VERSION 5.4 ;
NAMESCASESENSITIVE ON ;
BUSBITCHARS "[]" ;
DIVIDERCHAR "/" ;
UNITS
  DATABASE MICRONS 2000 ;
END UNITS
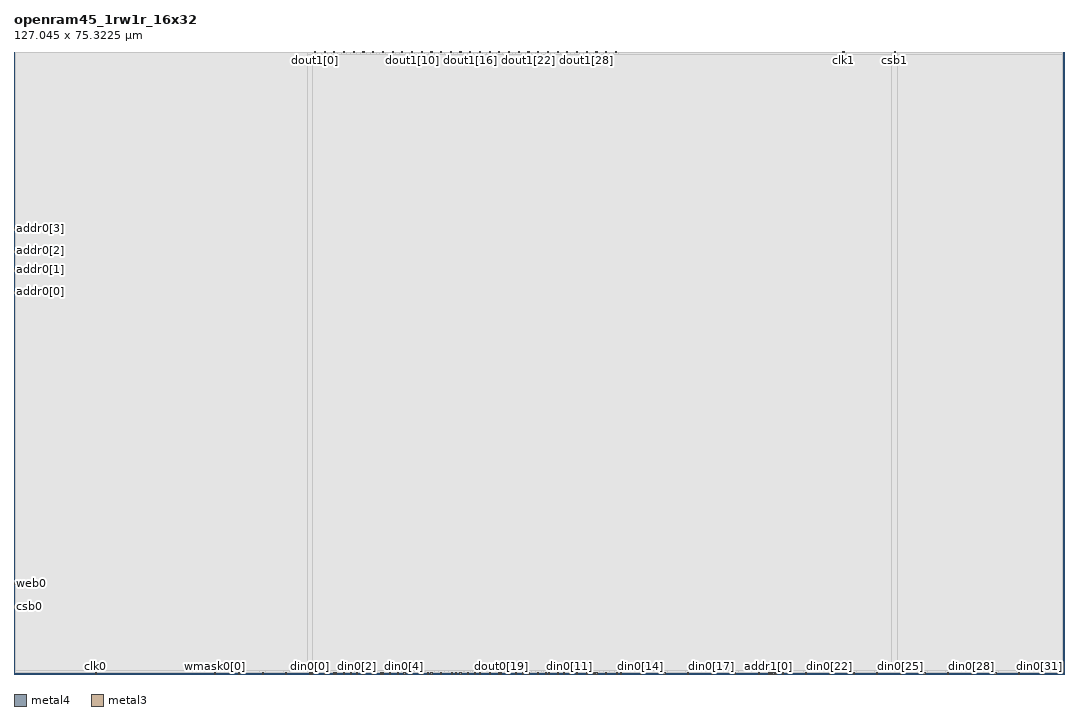
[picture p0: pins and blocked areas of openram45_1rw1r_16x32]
MACRO openram45_1rw1r_16x32
   CLASS BLOCK ;
   SIZE 127.045 BY 75.3225 ;
   SYMMETRY X Y R90 ;
   PIN din0[0]
      DIRECTION INPUT ;
      PORT
         LAYER metal4 ;
         RECT  35.7375 0.0 35.8775 0.14 ;
      END
   END din0[0]
   PIN din0[1]
      DIRECTION INPUT ;
      PORT
         LAYER metal4 ;
         RECT  38.5975 0.0 38.7375 0.14 ;
      END
   END din0[1]
   PIN din0[2]
      DIRECTION INPUT ;
      PORT
         LAYER metal4 ;
         RECT  41.4575 0.0 41.5975 0.14 ;
      END
   END din0[2]
   PIN din0[3]
      DIRECTION INPUT ;
      PORT
         LAYER metal4 ;
         RECT  44.3175 0.0 44.4575 0.14 ;
      END
   END din0[3]
   PIN din0[4]
      DIRECTION INPUT ;
      PORT
         LAYER metal4 ;
         RECT  47.1775 0.0 47.3175 0.14 ;
      END
   END din0[4]
   PIN din0[5]
      DIRECTION INPUT ;
      PORT
         LAYER metal4 ;
         RECT  50.0375 0.0 50.1775 0.14 ;
      END
   END din0[5]
   PIN din0[6]
      DIRECTION INPUT ;
      PORT
         LAYER metal4 ;
         RECT  52.8975 0.0 53.0375 0.14 ;
      END
   END din0[6]
   PIN din0[7]
      DIRECTION INPUT ;
      PORT
         LAYER metal4 ;
         RECT  55.7575 0.0 55.8975 0.14 ;
      END
   END din0[7]
   PIN din0[8]
      DIRECTION INPUT ;
      PORT
         LAYER metal4 ;
         RECT  58.6175 0.0 58.7575 0.14 ;
      END
   END din0[8]
   PIN din0[9]
      DIRECTION INPUT ;
      PORT
         LAYER metal4 ;
         RECT  61.4775 0.0 61.6175 0.14 ;
      END
   END din0[9]
   PIN din0[10]
      DIRECTION INPUT ;
      PORT
         LAYER metal4 ;
         RECT  64.3375 0.0 64.4775 0.14 ;
      END
   END din0[10]
   PIN din0[11]
      DIRECTION INPUT ;
      PORT
         LAYER metal4 ;
         RECT  67.1975 0.0 67.3375 0.14 ;
      END
   END din0[11]
   PIN din0[12]
      DIRECTION INPUT ;
      PORT
         LAYER metal4 ;
         RECT  70.0575 0.0 70.1975 0.14 ;
      END
   END din0[12]
   PIN din0[13]
      DIRECTION INPUT ;
      PORT
         LAYER metal4 ;
         RECT  72.9175 0.0 73.0575 0.14 ;
      END
   END din0[13]
   PIN din0[14]
      DIRECTION INPUT ;
      PORT
         LAYER metal4 ;
         RECT  75.7775 0.0 75.9175 0.14 ;
      END
   END din0[14]
   PIN din0[15]
      DIRECTION INPUT ;
      PORT
         LAYER metal4 ;
         RECT  78.6375 0.0 78.7775 0.14 ;
      END
   END din0[15]
   PIN din0[16]
      DIRECTION INPUT ;
      PORT
         LAYER metal4 ;
         RECT  81.4975 0.0 81.6375 0.14 ;
      END
   END din0[16]
   PIN din0[17]
      DIRECTION INPUT ;
      PORT
         LAYER metal4 ;
         RECT  84.3575 0.0 84.4975 0.14 ;
      END
   END din0[17]
   PIN din0[18]
      DIRECTION INPUT ;
      PORT
         LAYER metal4 ;
         RECT  87.2175 0.0 87.3575 0.14 ;
      END
   END din0[18]
   PIN din0[19]
      DIRECTION INPUT ;
      PORT
         LAYER metal4 ;
         RECT  90.0775 0.0 90.2175 0.14 ;
      END
   END din0[19]
   PIN din0[20]
      DIRECTION INPUT ;
      PORT
         LAYER metal4 ;
         RECT  92.9375 0.0 93.0775 0.14 ;
      END
   END din0[20]
   PIN din0[21]
      DIRECTION INPUT ;
      PORT
         LAYER metal4 ;
         RECT  95.7975 0.0 95.9375 0.14 ;
      END
   END din0[21]
   PIN din0[22]
      DIRECTION INPUT ;
      PORT
         LAYER metal4 ;
         RECT  98.6575 0.0 98.7975 0.14 ;
      END
   END din0[22]
   PIN din0[23]
      DIRECTION INPUT ;
      PORT
         LAYER metal4 ;
         RECT  101.5175 0.0 101.6575 0.14 ;
      END
   END din0[23]
   PIN din0[24]
      DIRECTION INPUT ;
      PORT
         LAYER metal4 ;
         RECT  104.3775 0.0 104.5175 0.14 ;
      END
   END din0[24]
   PIN din0[25]
      DIRECTION INPUT ;
      PORT
         LAYER metal4 ;
         RECT  107.2375 0.0 107.3775 0.14 ;
      END
   END din0[25]
   PIN din0[26]
      DIRECTION INPUT ;
      PORT
         LAYER metal4 ;
         RECT  110.0975 0.0 110.2375 0.14 ;
      END
   END din0[26]
   PIN din0[27]
      DIRECTION INPUT ;
      PORT
         LAYER metal4 ;
         RECT  112.9575 0.0 113.0975 0.14 ;
      END
   END din0[27]
   PIN din0[28]
      DIRECTION INPUT ;
      PORT
         LAYER metal4 ;
         RECT  115.8175 0.0 115.9575 0.14 ;
      END
   END din0[28]
   PIN din0[29]
      DIRECTION INPUT ;
      PORT
         LAYER metal4 ;
         RECT  118.6775 0.0 118.8175 0.14 ;
      END
   END din0[29]
   PIN din0[30]
      DIRECTION INPUT ;
      PORT
         LAYER metal4 ;
         RECT  121.5375 0.0 121.6775 0.14 ;
      END
   END din0[30]
   PIN din0[31]
      DIRECTION INPUT ;
      PORT
         LAYER metal4 ;
         RECT  124.3975 0.0 124.5375 0.14 ;
      END
   END din0[31]
   PIN addr0[0]
      DIRECTION INPUT ;
      PORT
         LAYER metal3 ;
         RECT  0.0 46.1875 0.14 46.3275 ;
      END
   END addr0[0]
   PIN addr0[1]
      DIRECTION INPUT ;
      PORT
         LAYER metal3 ;
         RECT  0.0 48.9175 0.14 49.0575 ;
      END
   END addr0[1]
   PIN addr0[2]
      DIRECTION INPUT ;
      PORT
         LAYER metal3 ;
         RECT  0.0 51.1275 0.14 51.2675 ;
      END
   END addr0[2]
   PIN addr0[3]
      DIRECTION INPUT ;
      PORT
         LAYER metal3 ;
         RECT  0.0 53.8575 0.14 53.9975 ;
      END
   END addr0[3]
   PIN addr1[0]
      DIRECTION INPUT ;
      PORT
         LAYER metal4 ;
         RECT  91.265 0.0 91.405 0.14 ;
      END
   END addr1[0]
   PIN addr1[1]
      DIRECTION INPUT ;
      PORT
         LAYER metal4 ;
         RECT  92.12 0.0 92.26 0.14 ;
      END
   END addr1[1]
   PIN addr1[2]
      DIRECTION INPUT ;
      PORT
         LAYER metal4 ;
         RECT  91.55 0.0 91.69 0.14 ;
      END
   END addr1[2]
   PIN addr1[3]
      DIRECTION INPUT ;
      PORT
         LAYER metal4 ;
         RECT  91.835 0.0 91.975 0.14 ;
      END
   END addr1[3]
   PIN csb0
      DIRECTION INPUT ;
      PORT
         LAYER metal3 ;
         RECT  0.0 8.0975 0.14 8.2375 ;
      END
   END csb0
   PIN csb1
      DIRECTION INPUT ;
      PORT
         LAYER metal4 ;
         RECT  106.4975 75.1825 106.6375 75.3225 ;
      END
   END csb1
   PIN web0
      DIRECTION INPUT ;
      PORT
         LAYER metal3 ;
         RECT  0.0 10.8275 0.14 10.9675 ;
      END
   END web0
   PIN clk0
      DIRECTION INPUT ;
      PORT
         LAYER metal4 ;
         RECT  9.84 0.0 9.98 0.14 ;
      END
   END clk0
   PIN clk1
      DIRECTION INPUT ;
      PORT
         LAYER metal4 ;
         RECT  100.3 75.1825 100.44 75.3225 ;
      END
   END clk1
   PIN wmask0[0]
      DIRECTION INPUT ;
      PORT
         LAYER metal4 ;
         RECT  24.2975 0.0 24.4375 0.14 ;
      END
   END wmask0[0]
   PIN wmask0[1]
      DIRECTION INPUT ;
      PORT
         LAYER metal4 ;
         RECT  27.1575 0.0 27.2975 0.14 ;
      END
   END wmask0[1]
   PIN wmask0[2]
      DIRECTION INPUT ;
      PORT
         LAYER metal4 ;
         RECT  30.0175 0.0 30.1575 0.14 ;
      END
   END wmask0[2]
   PIN wmask0[3]
      DIRECTION INPUT ;
      PORT
         LAYER metal4 ;
         RECT  32.8775 0.0 33.0175 0.14 ;
      END
   END wmask0[3]
   PIN dout0[0]
      DIRECTION OUTPUT ;
      PORT
         LAYER metal4 ;
         RECT  36.025 0.0 36.165 0.14 ;
      END
   END dout0[0]
   PIN dout0[1]
      DIRECTION OUTPUT ;
      PORT
         LAYER metal4 ;
         RECT  37.5125 0.0 37.6525 0.14 ;
      END
   END dout0[1]
   PIN dout0[2]
      DIRECTION OUTPUT ;
      PORT
         LAYER metal4 ;
         RECT  38.8825 0.0 39.0225 0.14 ;
      END
   END dout0[2]
   PIN dout0[3]
      DIRECTION OUTPUT ;
      PORT
         LAYER metal4 ;
         RECT  39.8625 0.0 40.0025 0.14 ;
      END
   END dout0[3]
   PIN dout0[4]
      DIRECTION OUTPUT ;
      PORT
         LAYER metal4 ;
         RECT  40.7 0.0 40.84 0.14 ;
      END
   END dout0[4]
   PIN dout0[5]
      DIRECTION OUTPUT ;
      PORT
         LAYER metal4 ;
         RECT  42.2125 0.0 42.3525 0.14 ;
      END
   END dout0[5]
   PIN dout0[6]
      DIRECTION OUTPUT ;
      PORT
         LAYER metal4 ;
         RECT  43.3875 0.0 43.5275 0.14 ;
      END
   END dout0[6]
   PIN dout0[7]
      DIRECTION OUTPUT ;
      PORT
         LAYER metal4 ;
         RECT  44.6025 0.0 44.7425 0.14 ;
      END
   END dout0[7]
   PIN dout0[8]
      DIRECTION OUTPUT ;
      PORT
         LAYER metal4 ;
         RECT  45.425 0.0 45.565 0.14 ;
      END
   END dout0[8]
   PIN dout0[9]
      DIRECTION OUTPUT ;
      PORT
         LAYER metal4 ;
         RECT  46.42 0.0 46.56 0.14 ;
      END
   END dout0[9]
   PIN dout0[10]
      DIRECTION OUTPUT ;
      PORT
         LAYER metal4 ;
         RECT  48.0875 0.0 48.2275 0.14 ;
      END
   END dout0[10]
   PIN dout0[11]
      DIRECTION OUTPUT ;
      PORT
         LAYER metal4 ;
         RECT  49.2625 0.0 49.4025 0.14 ;
      END
   END dout0[11]
   PIN dout0[12]
      DIRECTION OUTPUT ;
      PORT
         LAYER metal4 ;
         RECT  50.4375 0.0 50.5775 0.14 ;
      END
   END dout0[12]
   PIN dout0[13]
      DIRECTION OUTPUT ;
      PORT
         LAYER metal4 ;
         RECT  51.6125 0.0 51.7525 0.14 ;
      END
   END dout0[13]
   PIN dout0[14]
      DIRECTION OUTPUT ;
      PORT
         LAYER metal4 ;
         RECT  53.36 0.0 53.5 0.14 ;
      END
   END dout0[14]
   PIN dout0[15]
      DIRECTION OUTPUT ;
      PORT
         LAYER metal4 ;
         RECT  53.9625 0.0 54.1025 0.14 ;
      END
   END dout0[15]
   PIN dout0[16]
      DIRECTION OUTPUT ;
      PORT
         LAYER metal4 ;
         RECT  54.825 0.0 54.965 0.14 ;
      END
   END dout0[16]
   PIN dout0[17]
      DIRECTION OUTPUT ;
      PORT
         LAYER metal4 ;
         RECT  56.3125 0.0 56.4525 0.14 ;
      END
   END dout0[17]
   PIN dout0[18]
      DIRECTION OUTPUT ;
      PORT
         LAYER metal4 ;
         RECT  57.4875 0.0 57.6275 0.14 ;
      END
   END dout0[18]
   PIN dout0[19]
      DIRECTION OUTPUT ;
      PORT
         LAYER metal4 ;
         RECT  58.9025 0.0 59.0425 0.14 ;
      END
   END dout0[19]
   PIN dout0[20]
      DIRECTION OUTPUT ;
      PORT
         LAYER metal4 ;
         RECT  59.8375 0.0 59.9775 0.14 ;
      END
   END dout0[20]
   PIN dout0[21]
      DIRECTION OUTPUT ;
      PORT
         LAYER metal4 ;
         RECT  60.72 0.0 60.86 0.14 ;
      END
   END dout0[21]
   PIN dout0[22]
      DIRECTION OUTPUT ;
      PORT
         LAYER metal4 ;
         RECT  62.1875 0.0 62.3275 0.14 ;
      END
   END dout0[22]
   PIN dout0[23]
      DIRECTION OUTPUT ;
      PORT
         LAYER metal4 ;
         RECT  63.3625 0.0 63.5025 0.14 ;
      END
   END dout0[23]
   PIN dout0[24]
      DIRECTION OUTPUT ;
      PORT
         LAYER metal4 ;
         RECT  64.6225 0.0 64.7625 0.14 ;
      END
   END dout0[24]
   PIN dout0[25]
      DIRECTION OUTPUT ;
      PORT
         LAYER metal4 ;
         RECT  65.7125 0.0 65.8525 0.14 ;
      END
   END dout0[25]
   PIN dout0[26]
      DIRECTION OUTPUT ;
      PORT
         LAYER metal4 ;
         RECT  66.44 0.0 66.58 0.14 ;
      END
   END dout0[26]
   PIN dout0[27]
      DIRECTION OUTPUT ;
      PORT
         LAYER metal4 ;
         RECT  68.0625 0.0 68.2025 0.14 ;
      END
   END dout0[27]
   PIN dout0[28]
      DIRECTION OUTPUT ;
      PORT
         LAYER metal4 ;
         RECT  69.2375 0.0 69.3775 0.14 ;
      END
   END dout0[28]
   PIN dout0[29]
      DIRECTION OUTPUT ;
      PORT
         LAYER metal4 ;
         RECT  70.4125 0.0 70.5525 0.14 ;
      END
   END dout0[29]
   PIN dout0[30]
      DIRECTION OUTPUT ;
      PORT
         LAYER metal4 ;
         RECT  71.5875 0.0 71.7275 0.14 ;
      END
   END dout0[30]
   PIN dout0[31]
      DIRECTION OUTPUT ;
      PORT
         LAYER metal4 ;
         RECT  73.335 0.0 73.475 0.14 ;
      END
   END dout0[31]
   PIN dout1[0]
      DIRECTION OUTPUT ;
      PORT
         LAYER metal4 ;
         RECT  36.3375 75.1825 36.4775 75.3225 ;
      END
   END dout1[0]
   PIN dout1[1]
      DIRECTION OUTPUT ;
      PORT
         LAYER metal4 ;
         RECT  37.5125 75.1825 37.6525 75.3225 ;
      END
   END dout1[1]
   PIN dout1[2]
      DIRECTION OUTPUT ;
      PORT
         LAYER metal4 ;
         RECT  38.6875 75.1825 38.8275 75.3225 ;
      END
   END dout1[2]
   PIN dout1[3]
      DIRECTION OUTPUT ;
      PORT
         LAYER metal4 ;
         RECT  39.8625 75.1825 40.0025 75.3225 ;
      END
   END dout1[3]
   PIN dout1[4]
      DIRECTION OUTPUT ;
      PORT
         LAYER metal4 ;
         RECT  41.0375 75.1825 41.1775 75.3225 ;
      END
   END dout1[4]
   PIN dout1[5]
      DIRECTION OUTPUT ;
      PORT
         LAYER metal4 ;
         RECT  42.2125 75.1825 42.3525 75.3225 ;
      END
   END dout1[5]
   PIN dout1[6]
      DIRECTION OUTPUT ;
      PORT
         LAYER metal4 ;
         RECT  43.3875 75.1825 43.5275 75.3225 ;
      END
   END dout1[6]
   PIN dout1[7]
      DIRECTION OUTPUT ;
      PORT
         LAYER metal4 ;
         RECT  44.5625 75.1825 44.7025 75.3225 ;
      END
   END dout1[7]
   PIN dout1[8]
      DIRECTION OUTPUT ;
      PORT
         LAYER metal4 ;
         RECT  45.7375 75.1825 45.8775 75.3225 ;
      END
   END dout1[8]
   PIN dout1[9]
      DIRECTION OUTPUT ;
      PORT
         LAYER metal4 ;
         RECT  46.9125 75.1825 47.0525 75.3225 ;
      END
   END dout1[9]
   PIN dout1[10]
      DIRECTION OUTPUT ;
      PORT
         LAYER metal4 ;
         RECT  48.0875 75.1825 48.2275 75.3225 ;
      END
   END dout1[10]
   PIN dout1[11]
      DIRECTION OUTPUT ;
      PORT
         LAYER metal4 ;
         RECT  49.2625 75.1825 49.4025 75.3225 ;
      END
   END dout1[11]
   PIN dout1[12]
      DIRECTION OUTPUT ;
      PORT
         LAYER metal4 ;
         RECT  50.4375 75.1825 50.5775 75.3225 ;
      END
   END dout1[12]
   PIN dout1[13]
      DIRECTION OUTPUT ;
      PORT
         LAYER metal4 ;
         RECT  51.6125 75.1825 51.7525 75.3225 ;
      END
   END dout1[13]
   PIN dout1[14]
      DIRECTION OUTPUT ;
      PORT
         LAYER metal4 ;
         RECT  52.7875 75.1825 52.9275 75.3225 ;
      END
   END dout1[14]
   PIN dout1[15]
      DIRECTION OUTPUT ;
      PORT
         LAYER metal4 ;
         RECT  53.9625 75.1825 54.1025 75.3225 ;
      END
   END dout1[15]
   PIN dout1[16]
      DIRECTION OUTPUT ;
      PORT
         LAYER metal4 ;
         RECT  55.1375 75.1825 55.2775 75.3225 ;
      END
   END dout1[16]
   PIN dout1[17]
      DIRECTION OUTPUT ;
      PORT
         LAYER metal4 ;
         RECT  56.3125 75.1825 56.4525 75.3225 ;
      END
   END dout1[17]
   PIN dout1[18]
      DIRECTION OUTPUT ;
      PORT
         LAYER metal4 ;
         RECT  57.4875 75.1825 57.6275 75.3225 ;
      END
   END dout1[18]
   PIN dout1[19]
      DIRECTION OUTPUT ;
      PORT
         LAYER metal4 ;
         RECT  58.6625 75.1825 58.8025 75.3225 ;
      END
   END dout1[19]
   PIN dout1[20]
      DIRECTION OUTPUT ;
      PORT
         LAYER metal4 ;
         RECT  59.8375 75.1825 59.9775 75.3225 ;
      END
   END dout1[20]
   PIN dout1[21]
      DIRECTION OUTPUT ;
      PORT
         LAYER metal4 ;
         RECT  61.0125 75.1825 61.1525 75.3225 ;
      END
   END dout1[21]
   PIN dout1[22]
      DIRECTION OUTPUT ;
      PORT
         LAYER metal4 ;
         RECT  62.1875 75.1825 62.3275 75.3225 ;
      END
   END dout1[22]
   PIN dout1[23]
      DIRECTION OUTPUT ;
      PORT
         LAYER metal4 ;
         RECT  63.3625 75.1825 63.5025 75.3225 ;
      END
   END dout1[23]
   PIN dout1[24]
      DIRECTION OUTPUT ;
      PORT
         LAYER metal4 ;
         RECT  64.5375 75.1825 64.6775 75.3225 ;
      END
   END dout1[24]
   PIN dout1[25]
      DIRECTION OUTPUT ;
      PORT
         LAYER metal4 ;
         RECT  65.7125 75.1825 65.8525 75.3225 ;
      END
   END dout1[25]
   PIN dout1[26]
      DIRECTION OUTPUT ;
      PORT
         LAYER metal4 ;
         RECT  66.8875 75.1825 67.0275 75.3225 ;
      END
   END dout1[26]
   PIN dout1[27]
      DIRECTION OUTPUT ;
      PORT
         LAYER metal4 ;
         RECT  68.0625 75.1825 68.2025 75.3225 ;
      END
   END dout1[27]
   PIN dout1[28]
      DIRECTION OUTPUT ;
      PORT
         LAYER metal4 ;
         RECT  69.2375 75.1825 69.3775 75.3225 ;
      END
   END dout1[28]
   PIN dout1[29]
      DIRECTION OUTPUT ;
      PORT
         LAYER metal4 ;
         RECT  70.4125 75.1825 70.5525 75.3225 ;
      END
   END dout1[29]
   PIN dout1[30]
      DIRECTION OUTPUT ;
      PORT
         LAYER metal4 ;
         RECT  71.5875 75.1825 71.7275 75.3225 ;
      END
   END dout1[30]
   PIN dout1[31]
      DIRECTION OUTPUT ;
      PORT
         LAYER metal4 ;
         RECT  72.7625 75.1825 72.9025 75.3225 ;
      END
   END dout1[31]
   PIN vdd
      DIRECTION INOUT ;
      USE POWER ; 
      SHAPE ABUTMENT ; 
      PORT
      END
   END vdd
   PIN gnd
      DIRECTION INOUT ;
      USE GROUND ; 
      SHAPE ABUTMENT ; 
      PORT
      END
   END gnd
   OBS
   LAYER  metal1 ;
      RECT  0.14 0.14 126.905 75.1825 ;
   LAYER  metal2 ;
      RECT  0.14 0.14 126.905 75.1825 ;
   LAYER  metal3 ;
      RECT  0.28 0.14 126.905 46.0475 ;
      RECT  0.28 46.0475 126.905 46.4675 ;
      RECT  0.28 46.4675 126.905 75.1825 ;
      RECT  0.14 46.4675 0.28 48.7775 ;
      RECT  0.14 49.1975 0.28 50.9875 ;
      RECT  0.14 51.4075 0.28 53.7175 ;
      RECT  0.14 54.1375 0.28 75.1825 ;
      RECT  0.14 0.14 0.28 7.9575 ;
      RECT  0.14 8.3775 0.28 10.6875 ;
      RECT  0.14 11.1075 0.28 46.0475 ;
   LAYER  metal4 ;
      RECT  0.14 0.42 35.4575 75.1825 ;
      RECT  76.1975 0.14 78.3575 0.42 ;
      RECT  79.0575 0.14 81.2175 0.42 ;
      RECT  81.9175 0.14 84.0775 0.42 ;
      RECT  84.7775 0.14 86.9375 0.42 ;
      RECT  87.6375 0.14 89.7975 0.42 ;
      RECT  93.3575 0.14 95.5175 0.42 ;
      RECT  96.2175 0.14 98.3775 0.42 ;
      RECT  99.0775 0.14 101.2375 0.42 ;
      RECT  101.9375 0.14 104.0975 0.42 ;
      RECT  104.7975 0.14 106.9575 0.42 ;
      RECT  107.6575 0.14 109.8175 0.42 ;
      RECT  110.5175 0.14 112.6775 0.42 ;
      RECT  113.3775 0.14 115.5375 0.42 ;
      RECT  116.2375 0.14 118.3975 0.42 ;
      RECT  119.0975 0.14 121.2575 0.42 ;
      RECT  121.9575 0.14 124.1175 0.42 ;
      RECT  124.8175 0.14 126.905 0.42 ;
      RECT  90.4975 0.14 90.985 0.42 ;
      RECT  92.54 0.14 92.6575 0.42 ;
      RECT  36.1575 0.42 106.2175 74.9025 ;
      RECT  106.2175 0.42 106.9175 74.9025 ;
      RECT  106.9175 0.42 126.905 74.9025 ;
      RECT  106.9175 74.9025 126.905 75.1825 ;
      RECT  0.14 0.14 9.56 0.42 ;
      RECT  100.72 74.9025 106.2175 75.1825 ;
      RECT  10.26 0.14 24.0175 0.42 ;
      RECT  24.7175 0.14 26.8775 0.42 ;
      RECT  27.5775 0.14 29.7375 0.42 ;
      RECT  30.4375 0.14 32.5975 0.42 ;
      RECT  33.2975 0.14 35.4575 0.42 ;
      RECT  36.445 0.14 37.2325 0.42 ;
      RECT  37.9325 0.14 38.3175 0.42 ;
      RECT  39.3025 0.14 39.5825 0.42 ;
      RECT  40.2825 0.14 40.42 0.42 ;
      RECT  41.12 0.14 41.1775 0.42 ;
      RECT  41.8775 0.14 41.9325 0.42 ;
      RECT  42.6325 0.14 43.1075 0.42 ;
      RECT  43.8075 0.14 44.0375 0.42 ;
      RECT  45.0225 0.14 45.145 0.42 ;
      RECT  45.845 0.14 46.14 0.42 ;
      RECT  46.84 0.14 46.8975 0.42 ;
      RECT  47.5975 0.14 47.8075 0.42 ;
      RECT  48.5075 0.14 48.9825 0.42 ;
      RECT  49.6825 0.14 49.7575 0.42 ;
      RECT  50.8575 0.14 51.3325 0.42 ;
      RECT  52.0325 0.14 52.6175 0.42 ;
      RECT  54.3825 0.14 54.545 0.42 ;
      RECT  55.245 0.14 55.4775 0.42 ;
      RECT  56.7325 0.14 57.2075 0.42 ;
      RECT  57.9075 0.14 58.3375 0.42 ;
      RECT  59.3225 0.14 59.5575 0.42 ;
      RECT  60.2575 0.14 60.44 0.42 ;
      RECT  61.14 0.14 61.1975 0.42 ;
      RECT  61.8975 0.14 61.9075 0.42 ;
      RECT  62.6075 0.14 63.0825 0.42 ;
      RECT  63.7825 0.14 64.0575 0.42 ;
      RECT  65.0425 0.14 65.4325 0.42 ;
      RECT  66.1325 0.14 66.16 0.42 ;
      RECT  66.86 0.14 66.9175 0.42 ;
      RECT  67.6175 0.14 67.7825 0.42 ;
      RECT  68.4825 0.14 68.9575 0.42 ;
      RECT  69.6575 0.14 69.7775 0.42 ;
      RECT  70.8325 0.14 71.3075 0.42 ;
      RECT  72.0075 0.14 72.6375 0.42 ;
      RECT  73.755 0.14 75.4975 0.42 ;
      RECT  35.4575 0.42 36.0575 74.9025 ;
      RECT  35.4575 74.9025 36.0575 75.1825 ;
      RECT  36.0575 0.42 36.1575 74.9025 ;
      RECT  36.7575 74.9025 37.2325 75.1825 ;
      RECT  37.9325 74.9025 38.4075 75.1825 ;
      RECT  39.1075 74.9025 39.5825 75.1825 ;
      RECT  40.2825 74.9025 40.7575 75.1825 ;
      RECT  41.4575 74.9025 41.9325 75.1825 ;
      RECT  42.6325 74.9025 43.1075 75.1825 ;
      RECT  43.8075 74.9025 44.2825 75.1825 ;
      RECT  44.9825 74.9025 45.4575 75.1825 ;
      RECT  46.1575 74.9025 46.6325 75.1825 ;
      RECT  47.3325 74.9025 47.8075 75.1825 ;
      RECT  48.5075 74.9025 48.9825 75.1825 ;
      RECT  49.6825 74.9025 50.1575 75.1825 ;
      RECT  50.8575 74.9025 51.3325 75.1825 ;
      RECT  52.0325 74.9025 52.5075 75.1825 ;
      RECT  53.2075 74.9025 53.6825 75.1825 ;
      RECT  54.3825 74.9025 54.8575 75.1825 ;
      RECT  55.5575 74.9025 56.0325 75.1825 ;
      RECT  56.7325 74.9025 57.2075 75.1825 ;
      RECT  57.9075 74.9025 58.3825 75.1825 ;
      RECT  59.0825 74.9025 59.5575 75.1825 ;
      RECT  60.2575 74.9025 60.7325 75.1825 ;
      RECT  61.4325 74.9025 61.9075 75.1825 ;
      RECT  62.6075 74.9025 63.0825 75.1825 ;
      RECT  63.7825 74.9025 64.2575 75.1825 ;
      RECT  64.9575 74.9025 65.4325 75.1825 ;
      RECT  66.1325 74.9025 66.6075 75.1825 ;
      RECT  67.3075 74.9025 67.7825 75.1825 ;
      RECT  68.4825 74.9025 68.9575 75.1825 ;
      RECT  69.6575 74.9025 70.1325 75.1825 ;
      RECT  70.8325 74.9025 71.3075 75.1825 ;
      RECT  72.0075 74.9025 72.4825 75.1825 ;
      RECT  73.1825 74.9025 100.02 75.1825 ;
   END
END    openram45_1rw1r_16x32
END    LIBRARY
